VERSION 5.8 ;
BUSBITCHARS "[]" ;
DIVIDERCHAR "/" ;
UNITS
    DATABASE MICRONS 1000 ;
END UNITS

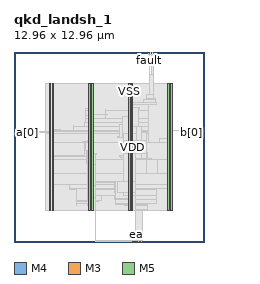
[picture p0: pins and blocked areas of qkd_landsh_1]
MACRO qkd_landsh_1
  FOREIGN qkd_landsh_1 0 0 ;
  CLASS BLOCK ;
  SIZE 12.96 BY 12.96 ;
  PIN a[0]
    DIRECTION INPUT ;
    USE SIGNAL ;
    PORT
      LAYER M4 ;
        RECT  0 7.488 0.084 7.512 ;
    END
  END a[0]
  PIN b[0]
    DIRECTION OUTPUT ;
    USE SIGNAL ;
    PORT
      LAYER M4 ;
        RECT  12.876 7.488 12.96 7.512 ;
    END
  END b[0]
  PIN ck
    DIRECTION INPUT ;
    USE SIGNAL ;
    PORT
      LAYER M3 ;
        RECT  8.1 0 8.118 0.037 ;
    END
  END ck
  PIN ckf
    DIRECTION INPUT ;
    USE SIGNAL ;
    PORT
      LAYER M3 ;
        RECT  8.208 0 8.226 0.037 ;
    END
  END ckf
  PIN ea
    DIRECTION INPUT ;
    USE SIGNAL ;
    PORT
      LAYER M3 ;
        RECT  8.316 0 8.334 0.037 ;
    END
  END ea
  PIN fault
    DIRECTION OUTPUT ;
    USE SIGNAL ;
    PORT
      LAYER M5 ;
        RECT  9.216 12.876 9.24 12.96 ;
    END
  END fault
  PIN k0
    DIRECTION INPUT ;
    USE SIGNAL ;
    PORT
      LAYER M3 ;
        RECT  8.424 0 8.442 0.037 ;
    END
  END k0
  PIN k1
    DIRECTION INPUT ;
    USE SIGNAL ;
    PORT
      LAYER M3 ;
        RECT  8.532 0 8.55 0.037 ;
    END
  END k1
  PIN k2
    DIRECTION INPUT ;
    USE SIGNAL ;
    PORT
      LAYER M3 ;
        RECT  8.64 0 8.658 0.037 ;
    END
  END k2
  PIN rs
    DIRECTION INPUT ;
    USE SIGNAL ;
    PORT
      LAYER M3 ;
        RECT  8.748 0 8.766 0.037 ;
    END
  END rs
  PIN tie_hi
    DIRECTION OUTPUT ;
    USE SIGNAL ;
    PORT
      LAYER M5 ;
        RECT  9.36 12.876 9.384 12.96 ;
    END
  END tie_hi
  PIN tie_lo
    DIRECTION OUTPUT ;
    USE SIGNAL ;
    PORT
      LAYER M5 ;
        RECT  9.504 12.876 9.528 12.96 ;
    END
  END tie_lo
  PIN VDD
    DIRECTION INOUT ;
    USE POWER ;
    PORT
      LAYER M5 ;
        RECT  10.692 2.151 10.812 10.809 ;
        RECT  7.992 2.151 8.112 10.809 ;
        RECT  5.292 2.151 5.412 10.809 ;
        RECT  2.592 2.151 2.712 10.809 ;
    END
  END VDD
  PIN VSS
    DIRECTION INOUT ;
    USE GROUND ;
    PORT
      LAYER M5 ;
        RECT  10.5 2.137 10.62 10.823 ;
        RECT  7.8 2.137 7.92 10.823 ;
        RECT  5.1 2.137 5.22 10.823 ;
        RECT  2.4 2.137 2.52 10.823 ;
    END
  END VSS
  OBS
    LAYER RVTN ;
     RECT  2.16 2.16 10.8 2.295 ;
     RECT  2.16 2.565 10.8 2.835 ;
     RECT  2.16 3.105 10.8 3.375 ;
     RECT  2.16 3.645 10.8 3.915 ;
     RECT  2.16 4.185 10.8 4.455 ;
     RECT  2.16 4.725 10.8 4.995 ;
     RECT  2.16 5.265 10.8 5.535 ;
     RECT  2.16 5.805 10.8 6.075 ;
     RECT  2.16 6.345 10.8 6.615 ;
     RECT  2.16 6.885 10.8 7.155 ;
     RECT  2.16 7.425 10.8 7.695 ;
     RECT  2.16 7.965 10.8 8.235 ;
     RECT  2.16 8.505 10.8 8.775 ;
     RECT  2.16 9.045 10.8 9.315 ;
     RECT  2.16 9.585 10.8 9.855 ;
     RECT  2.16 10.125 10.8 10.395 ;
     RECT  2.16 10.665 10.8 10.8 ;
    LAYER RVTP ;
     RECT  2.16 2.295 10.8 2.565 ;
     RECT  2.16 2.835 10.8 3.105 ;
     RECT  2.16 3.375 10.8 3.645 ;
     RECT  2.16 3.915 10.8 4.185 ;
     RECT  2.16 4.455 10.8 4.725 ;
     RECT  2.16 4.995 10.8 5.265 ;
     RECT  2.16 5.535 10.8 5.805 ;
     RECT  2.16 6.075 10.8 6.345 ;
     RECT  2.16 6.615 10.8 6.885 ;
     RECT  2.16 7.155 10.8 7.425 ;
     RECT  2.16 7.695 10.8 7.965 ;
     RECT  2.16 8.235 10.8 8.505 ;
     RECT  2.16 8.775 10.8 9.045 ;
     RECT  2.16 9.315 10.8 9.585 ;
     RECT  2.16 9.855 10.8 10.125 ;
     RECT  2.16 10.395 10.8 10.665 ;
    LAYER M1 ;
     RECT  2.16 2.151 10.8 10.809 ;
    LAYER M2 ;
     RECT  7.915 0.036 8.231 0.054 ;
     RECT  2.16 2.151 10.8 10.809 ;
     RECT  10.8 2.421 10.812 10.539 ;
     RECT  10.812 7.596 11.975 7.614 ;
    LAYER M3 ;
     RECT  8.1 0.012 8.766 0.031 ;
     RECT  7.92 0.031 8.766 0.077 ;
     RECT  8.1 0.077 8.766 0.125 ;
     RECT  8.316 0.125 8.766 2.143 ;
     RECT  7.815 2.143 8.766 2.227 ;
     RECT  2.415 2.143 2.505 2.413 ;
     RECT  5.115 2.143 5.205 2.413 ;
     RECT  10.515 2.143 10.605 2.413 ;
     RECT  7.815 2.227 9.09 2.461 ;
     RECT  5.115 2.413 5.397 2.497 ;
     RECT  7.56 2.461 9.09 2.533 ;
     RECT  4.248 2.497 4.266 2.641 ;
     RECT  5.04 2.497 5.397 2.641 ;
     RECT  6.912 2.533 9.09 2.641 ;
     RECT  4.248 2.641 5.526 2.767 ;
     RECT  4.248 2.767 5.742 2.803 ;
     RECT  6.912 2.641 9.738 2.875 ;
     RECT  4.248 2.803 5.958 3.181 ;
     RECT  6.84 2.875 9.738 3.181 ;
     RECT  4.248 3.181 9.738 3.577 ;
     RECT  3.816 3.577 9.738 3.649 ;
     RECT  10.515 2.413 10.797 3.649 ;
     RECT  2.415 2.413 2.697 3.955 ;
     RECT  3.816 3.649 10.797 3.955 ;
     RECT  2.415 3.955 10.797 4.649 ;
     RECT  2.415 4.649 9.018 5.611 ;
     RECT  9.792 4.649 10.797 5.611 ;
     RECT  2.415 5.611 10.797 6.809 ;
     RECT  9.936 6.809 10.797 7.079 ;
     RECT  2.415 6.809 9.198 7.393 ;
     RECT  2.304 7.393 9.198 7.517 ;
     RECT  2.415 7.517 9.198 7.619 ;
     RECT  11.952 7.483 11.97 7.619 ;
     RECT  2.415 7.619 3.186 7.655 ;
     RECT  4.032 7.619 9.198 7.889 ;
     RECT  4.032 7.889 4.05 7.925 ;
     RECT  4.788 7.889 9.198 8.159 ;
     RECT  4.86 8.159 9.198 8.429 ;
     RECT  4.86 8.429 5.454 8.609 ;
     RECT  4.896 8.609 5.454 8.969 ;
     RECT  6.228 8.429 9.198 8.969 ;
     RECT  6.228 8.969 6.246 9.041 ;
     RECT  4.896 8.969 5.397 9.113 ;
     RECT  7.815 8.969 9.198 9.391 ;
     RECT  7.815 9.391 9.702 9.509 ;
     RECT  7.815 9.509 9.666 9.545 ;
     RECT  8.82 9.545 9.666 9.689 ;
     RECT  9.036 9.689 9.666 9.779 ;
     RECT  9.036 9.779 9.558 9.815 ;
     RECT  9.036 9.815 9.522 10.085 ;
     RECT  2.415 7.655 2.697 10.547 ;
     RECT  5.115 9.113 5.397 10.547 ;
     RECT  7.815 9.545 8.097 10.547 ;
     RECT  10.515 7.079 10.797 10.547 ;
     RECT  2.415 10.547 2.505 10.817 ;
     RECT  5.115 10.547 5.205 10.817 ;
     RECT  7.815 10.547 7.905 10.817 ;
     RECT  10.515 10.547 10.605 10.817 ;
     RECT  9.252 10.085 9.522 11.453 ;
     RECT  9.252 11.453 9.27 12.845 ;
    LAYER M4 ;
     RECT  0.06 7.488 2.408 7.512 ;
     RECT  2.408 2.148 2.512 10.812 ;
     RECT  2.512 2.418 2.704 10.542 ;
     RECT  2.704 7.392 3.629 7.416 ;
     RECT  3.805 3.6 4.237 3.624 ;
     RECT  2.704 5.856 4.813 5.88 ;
     RECT  4.705 6.864 4.813 6.888 ;
     RECT  4.813 5.856 4.949 6.888 ;
     RECT  4.237 2.832 4.981 3.624 ;
     RECT  4.981 2.832 5.029 3.864 ;
     RECT  4.949 5.328 5.029 6.888 ;
     RECT  5.029 2.832 5.108 6.888 ;
     RECT  5.108 2.148 5.212 10.812 ;
     RECT  5.212 2.418 5.404 10.542 ;
     RECT  5.404 6 5.603 6.024 ;
     RECT  5.404 8.688 6.365 8.712 ;
     RECT  5.404 4.08 6.829 4.104 ;
     RECT  6.829 3.36 6.937 4.104 ;
     RECT  7.045 7.152 7.189 7.176 ;
     RECT  7.225 5.856 7.261 5.88 ;
     RECT  7.189 7.152 7.369 7.992 ;
     RECT  7.261 5.76 7.513 5.88 ;
     RECT  7.513 5.76 7.693 6.024 ;
     RECT  6.937 2.976 7.808 4.104 ;
     RECT  7.693 5.472 7.808 6.024 ;
     RECT  7.369 7.152 7.808 8.568 ;
     RECT  7.808 2.148 7.912 10.812 ;
     RECT  5.557 0.048 7.949 0.072 ;
     RECT  7.912 2.418 8.104 10.542 ;
     RECT  8.104 5.472 8.201 7.896 ;
     RECT  8.089 0.096 8.291 0.12 ;
     RECT  8.104 9.12 8.531 9.144 ;
     RECT  8.201 5.664 8.669 7.896 ;
     RECT  8.669 5.664 9.065 7.464 ;
     RECT  9.065 5.664 9.1 6.072 ;
     RECT  9.197 12.816 9.281 12.84 ;
     RECT  9.1 5.664 9.389 5.688 ;
     RECT  9.308 11.424 9.539 11.448 ;
     RECT  10.508 2.148 10.612 10.812 ;
     RECT  10.612 2.418 10.804 10.542 ;
     RECT  11.941 7.488 12.924 7.512 ;
    LAYER M5 ;
     RECT  5.568 0.037 5.592 2.137 ;
     RECT  8.256 0.085 8.28 2.137 ;
     RECT  2.4 2.137 2.52 2.151 ;
     RECT  10.5 2.137 10.62 2.151 ;
     RECT  5.1 2.137 5.592 3.061 ;
     RECT  7.8 2.137 8.28 3.157 ;
     RECT  7.44 3.157 8.28 3.349 ;
     RECT  4.992 3.061 5.592 3.875 ;
     RECT  7.056 3.349 8.28 4.115 ;
     RECT  5.1 3.875 5.592 5.317 ;
     RECT  4.992 5.317 5.592 6.035 ;
     RECT  7.44 4.115 8.28 6.037 ;
     RECT  4.992 6.035 5.412 6.229 ;
     RECT  4.848 6.229 5.412 6.803 ;
     RECT  4.992 6.803 5.412 6.899 ;
     RECT  7.44 6.037 9.048 6.899 ;
     RECT  7.44 6.899 8.376 7.427 ;
     RECT  7.8 7.427 8.376 7.861 ;
     RECT  7.8 7.861 8.52 9.155 ;
     RECT  2.4 2.151 2.712 10.809 ;
     RECT  5.1 6.899 5.412 10.809 ;
     RECT  7.8 9.155 8.112 10.809 ;
     RECT  10.5 2.151 10.812 10.809 ;
     RECT  2.4 10.809 2.52 10.823 ;
     RECT  5.1 10.809 5.22 10.823 ;
     RECT  7.8 10.809 7.92 10.823 ;
     RECT  10.5 10.809 10.62 10.823 ;
     RECT  9.36 11.413 9.528 12.805 ;
     RECT  9.216 12.805 9.528 12.944 ;
  END
END qkd_landsh_1
END LIBRARY
